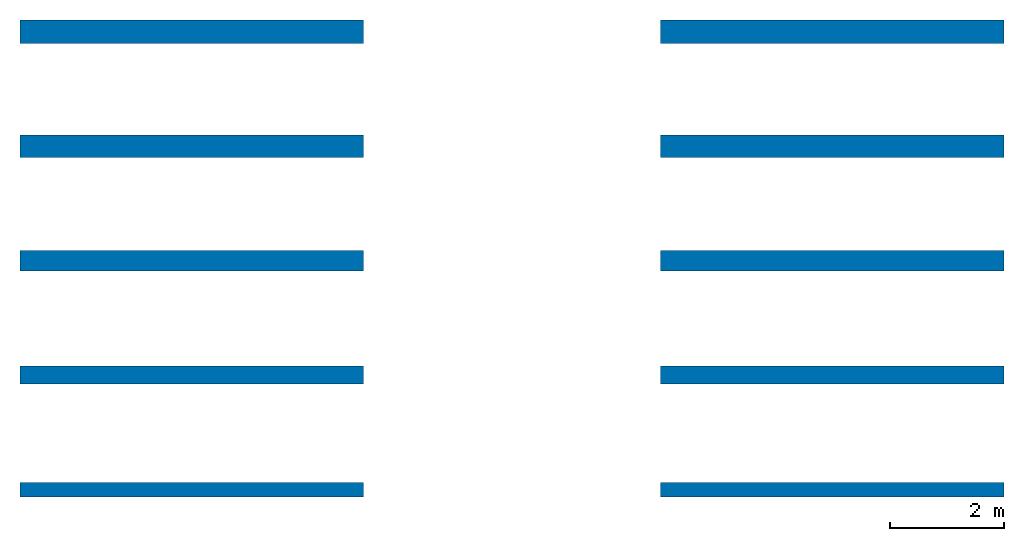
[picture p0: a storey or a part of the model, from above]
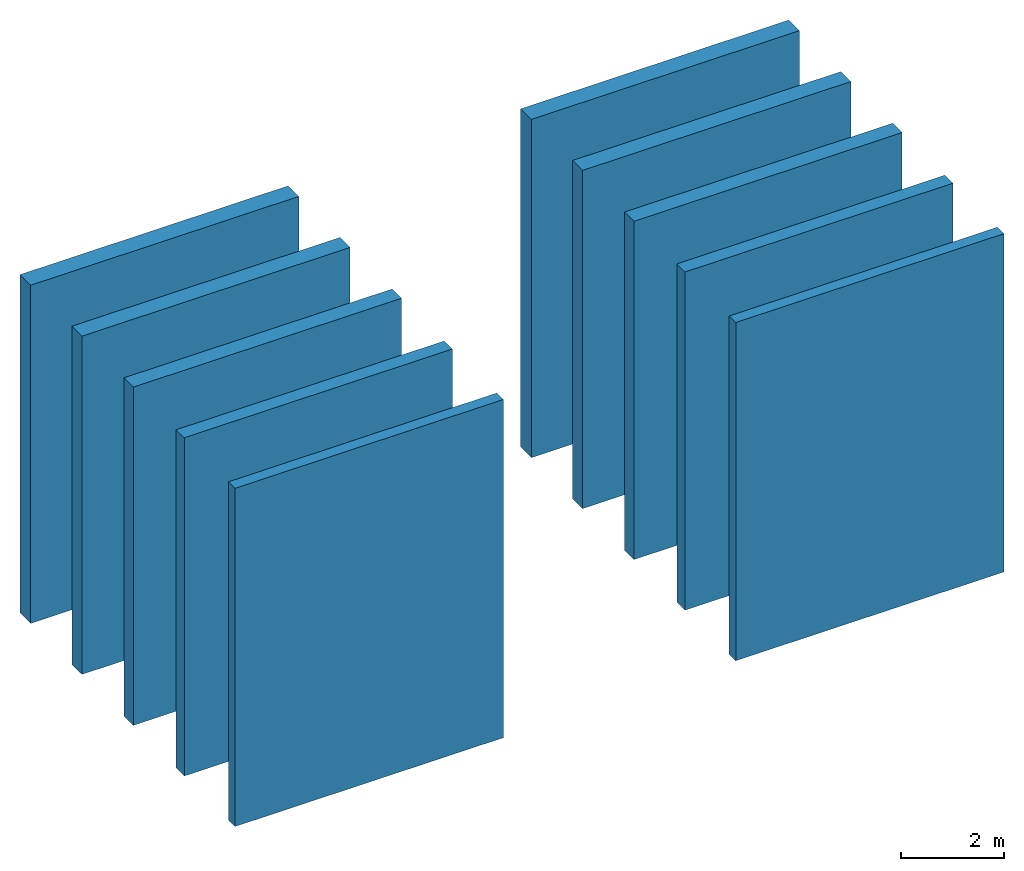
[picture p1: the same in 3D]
Properties of the parts of a building model (IFC2X3)

# File
Description: ViewDefinition [CoordinationView]
File name: Numero
Time: 2019-05-03T09:56:35
Written by: The EXPRESS Data Manager Version 5.02.0100.07 : 28 Aug 2013
Made in: 20150220_1215(x64) - Exporter 16.0.428.0 - Default UI
Comment: STEP Physical File produced by: The EXPRESS Data Manager Version 5.02.0100.07 : 28 Aug 2013 * Module: EDMstepFileFactory/EDMstandAlone * Creation date: Fri May 03 09:56:35 2019 * Host: HP-RS * Database: C:\Users\EKORU_~1\AppData\Local\Temp\{FCCCFBD5-6221-4E83-B3F0-1DA5C1BFEEF4}\ifc * Database version: 5507 * Database creation date: Fri May 03 09:56:35 2019 * Schema: IFC2X3 * Model: DataRepository.ifc * Model creation date: Fri May 03 09:56:35 2019 * Header model: DataRepository.ifc_HeaderModel * Header model creation date: Fri May 03 09:56:35 2019 * EDMuser: sdai-user * EDMgroup: sdai-group * License ID and type: 5605 : Permanent license. Expiry date: * EDMstepFileFactory options: 020000

# IfcProject, Numero
LongName: Nome; Phase: Stato

# IfcSite, Default
RefLatitude: 41, 47, 59, 999999; RefLongitude: 12, 35, 59, 999999; RefElevation: 0 mm
Altro - Categoria: Informazioni sul progetto; Data di consegna del progetto: Data; Indirizzo del progetto: Immettere l'indirizzo; Nome del cliente: Proprietario; Nome del progetto: Nome; Numero del progetto: Numero; Stato del progetto: Stato

# IfcBuilding
Pset_BuildingCommon - NumberOfStoreys: 1
Altro - Categoria: Informazioni sul progetto; Data di consegna del progetto: Data; Indirizzo del progetto: Immettere l'indirizzo; Nome del cliente: Proprietario; Nome del progetto: Nome; Numero del progetto: Numero; Stato del progetto: Stato

# IfcBuildingStorey, Livello 1
LongName: Livello 1; Elevation: 0 mm
Vincoli - Base quota altimetrica: Punto base progetto; Quota altimetrica: 0 mm
Altro - Categoria: Livelli; Famiglia: Livello: Estremità 8 mm; Famiglia e tipo: Livello: Estremità 8 mm; ID tipo: Livello: Estremità 8 mm; Tipo: Livello: Estremità 8 mm; Nome famiglia: Livello
Dati identità - Strutturale: no; Nome: Livello 1; Piano edificio: yes; Nome del tipo: Estremità 8 mm
Dimensioni - Altezza di calcolo: 0 mm
Grafica - Colore: 0; Modello di linea: Centro; Simbolo: Estremità del livello - Cerchio: Estremità del livello - Cerchio; Simbolo a estremità 1 per default: no; Simbolo a estremità 2 per default: yes; Spessore di linea: 1

# IfcWallStandardCase: Muro di base:Sistema GASBETON Sysmic sp. 254 mm muratura portante, Muro di base:Sistema GASBETON Sysmic sp. 254 mm muratura portante:139188
In: Livello 1
Type - PredefinedType: STANDARD; Material: GASBETON Multiraso interni 2 mm, GASBETON Incollarasa 5 mm, GASBETON Sysmic 240 mm, GASBETON Incollarasa 5 mm, GASBETON Multiraso interni 2 mm
Type - Altro - Categoria: Muri; Nome famiglia: Muro di base
Type - Costruzione - Funzione: Esterno; Ripiegatura agli inserti: Non ripiegare; Ripiegatura alle estremità: Nessuno; Larghezza: 254 mm
Type - Dati identità - Descrizione: Parete rifinita formata dalla seguente stratigrafia (dall'esterno verso l'interno): Multiraso interni, rete da intonaco GASBETON, Incollarasa, blocchi GASBETON Sysmic, Incollarasa, rete da intonaco GASBETON, Multira; Installation Guide: http://www.gasbeton.it/wp-content/uploads/2017/11/GASBETON-Guida-alla-progettazione.pdf; Modello: Soluzione muratura interna portante Gasbeton Sysmic; Nome del tipo: Sistema GASBETON Sysmic sp. 254 mm muratura portante; Product data url: www.gasbeton.it; Produttore: EKORU s.r.l.; Resistenza al fuoco: REI 180; EI 240; Euroclasse A1; Techinical data sheet: http://www.gasbeton.it/download/; URL: http://www.ekoru.it/; Youtube channel: https://www.youtube.com/user/bacchispa
Type - Generale - Edition number: 1; Manufacturer country: Italy; Manufacturer name: EKORU s.r.l.; Product family: walls
Type - Grafica - Colore del retino a dettaglio basso: 0
Type - Materiali e finiture - Materiale strutturale: GASBETON Sysmic; Material main: Autoclaved Aerated Concrete (AAC)
Type - Proprietà analitiche - Ruvidità: 2; Assorbimento: 0.7; Coefficiente di scambio termico (U): 0.41656; Massa termica: 499968; Resistenza termica (R): 2.40061
Altro - Famiglia: Muro di base: Sistema GASBETON Sysmic sp. 254 mm muratura portante; Famiglia e tipo: Muro di base: Sistema GASBETON Sysmic sp. 254 mm muratura portante; ID tipo: Muro di base: Sistema GASBETON Sysmic sp. 254 mm muratura portante; Tipo: Muro di base: Sistema GASBETON Sysmic sp. 254 mm muratura portante
Dimensioni - Area: 48 m2; Lunghezza: 6000 mm; Volume: 12.192 m3
Fasi - Fase di creazione: Fase 1
Strutturale - Attiva modello analitico: no; Strutturale: no; Utilizzo strutturale: Non portante
Vincoli - Delimita il locale: yes; Distanza estensione base: 0 mm; Distanza estensione superiore: 0 mm; La base è associata: no; La parte superiore è associata: no; Linea di ubicazione: Linea d'asse del muro; Offset base: 0 mm; Offset superiore: 0 mm; Relativo a massa: no; Vincolo di base: Livello: Livello 1; Altezza non collegata: 8000 mm
Pset_WallCommon - LoadBearing: no; ExtendToStructure: no; IsExternal: yes; Reference: Sistema GASBETON Sysmic sp. 254 mm muratura portante; FireRating: REI 180; EI 240; Euroclasse A1; ThermalTransmittance: 0.41656 kg/K/s3
Pset_ManufacturerTypeInformation - Manufacturer: EKORU s.r.l.

# IfcWallStandardCase: Muro di base:Sistema GASBETON Sysmic sp. 314 mm muratura portante, Muro di base:Sistema GASBETON Sysmic sp. 314 mm muratura portante:139180
In: Livello 1
Type - PredefinedType: STANDARD; Material: GASBETON Multiraso interni 2 mm, GASBETON Incollarasa 5 mm, GASBETON Sysmic 300 mm, GASBETON Incollarasa 5 mm, GASBETON Multiraso interni 2 mm
Type - Altro - Categoria: Muri; Nome famiglia: Muro di base
Type - Costruzione - Funzione: Esterno; Ripiegatura agli inserti: Non ripiegare; Ripiegatura alle estremità: Nessuno; Larghezza: 314 mm
Type - Dati identità - Descrizione: Parete rifinita formata dalla seguente stratigrafia (dall'esterno verso l'interno): Multiraso interni, rete da intonaco GASBETON, Incollarasa, blocchi GASBETON Sysmic, Incollarasa, rete da intonaco GASBETON, Multira; Installation Guide: http://www.gasbeton.it/wp-content/uploads/2017/11/GASBETON-Guida-alla-progettazione.pdf; Modello: Soluzione muratura interna portante Gasbeton Sysmic; Nome del tipo: Sistema GASBETON Sysmic sp. 314 mm muratura portante; Product data url: www.gasbeton.it; Produttore: EKORU s.r.l.; Resistenza al fuoco: REI 240; Euroclasse A1; Techinical data sheet: http://www.gasbeton.it/download/; URL: http://www.ekoru.it/; Youtube channel: https://www.youtube.com/user/bacchispa
Type - Generale - Edition number: 1; Manufacturer country: Italy; Manufacturer name: EKORU s.r.l.; Product family: walls
Type - Grafica - Colore del retino a dettaglio basso: 0
Type - Materiali e finiture - Materiale strutturale: GASBETON Sysmic; Material main: Autoclaved Aerated Concrete (AAC)
Type - Proprietà analitiche - Ruvidità: 2; Assorbimento: 0.7; Coefficiente di scambio termico (U): 0.334469; Massa termica: 621168; Resistenza termica (R): 2.98981
Altro - Famiglia: Muro di base: Sistema GASBETON Sysmic sp. 314 mm muratura portante; Famiglia e tipo: Muro di base: Sistema GASBETON Sysmic sp. 314 mm muratura portante; ID tipo: Muro di base: Sistema GASBETON Sysmic sp. 314 mm muratura portante; Tipo: Muro di base: Sistema GASBETON Sysmic sp. 314 mm muratura portante
Dimensioni - Area: 48 m2; Lunghezza: 6000 mm; Volume: 15.072 m3
Fasi - Fase di creazione: Fase 1
Strutturale - Attiva modello analitico: no; Strutturale: no; Utilizzo strutturale: Non portante
Vincoli - Delimita il locale: yes; Distanza estensione base: 0 mm; Distanza estensione superiore: 0 mm; La base è associata: no; La parte superiore è associata: no; Linea di ubicazione: Linea d'asse del muro; Offset base: 0 mm; Offset superiore: 0 mm; Relativo a massa: no; Vincolo di base: Livello: Livello 1; Altezza non collegata: 8000 mm
Pset_WallCommon - LoadBearing: no; ExtendToStructure: no; IsExternal: yes; Reference: Sistema GASBETON Sysmic sp. 314 mm muratura portante; FireRating: REI 240; Euroclasse A1; ThermalTransmittance: 0.334469 kg/K/s3
Pset_ManufacturerTypeInformation - Manufacturer: EKORU s.r.l.

# IfcWallStandardCase: Muro di base:Sistema GASBETON Sysmic sp. 364 mm muratura portante, Muro di base:Sistema GASBETON Sysmic sp. 364 mm muratura portante:139172
In: Livello 1
Type - PredefinedType: STANDARD; Material: GASBETON Multiraso interni 2 mm, GASBETON Incollarasa 5 mm, GASBETON Sysmic 350 mm, GASBETON Incollarasa 5 mm, GASBETON Multiraso interni 2 mm
Type - Altro - Categoria: Muri; Nome famiglia: Muro di base
Type - Costruzione - Funzione: Esterno; Ripiegatura agli inserti: Non ripiegare; Ripiegatura alle estremità: Nessuno; Larghezza: 364 mm
Type - Dati identità - Descrizione: Parete rifinita formata dalla seguente stratigrafia (dall'esterno verso l'interno): Multiraso interni, rete da intonaco GASBETON, Incollarasa, blocchi GASBETON Sysmic, Incollarasa, rete da intonaco GASBETON, Multira; Installation Guide: http://www.gasbeton.it/wp-content/uploads/2017/11/GASBETON-Guida-alla-progettazione.pdf; Modello: Soluzione muratura interna portante Gasbeton Sysmic; Nome del tipo: Sistema GASBETON Sysmic sp. 364 mm muratura portante; Product data url: www.gasbeton.it; Produttore: EKORU s.r.l.; Resistenza al fuoco: REI 240; Euroclasse A1; Techinical data sheet: http://www.gasbeton.it/download/; URL: http://www.ekoru.it/; Youtube channel: https://www.youtube.com/user/bacchispa
Type - Generale - Edition number: 1; Manufacturer country: Italy; Manufacturer name: EKORU s.r.l.; Product family: walls
Type - Grafica - Colore del retino a dettaglio basso: 0
Type - Materiali e finiture - Materiale strutturale: GASBETON Sysmic; Material main: Autoclaved Aerated Concrete (AAC)
Type - Proprietà analitiche - Ruvidità: 2; Assorbimento: 0.7; Coefficiente di scambio termico (U): 0.287289; Massa termica: 722168; Resistenza termica (R): 3.48081
Altro - Famiglia: Muro di base: Sistema GASBETON Sysmic sp. 364 mm muratura portante; Famiglia e tipo: Muro di base: Sistema GASBETON Sysmic sp. 364 mm muratura portante; ID tipo: Muro di base: Sistema GASBETON Sysmic sp. 364 mm muratura portante; Tipo: Muro di base: Sistema GASBETON Sysmic sp. 364 mm muratura portante
Dimensioni - Area: 48 m2; Lunghezza: 6000 mm; Volume: 17.472 m3
Fasi - Fase di creazione: Fase 1
Strutturale - Attiva modello analitico: no; Strutturale: no; Utilizzo strutturale: Non portante
Vincoli - Delimita il locale: yes; Distanza estensione base: 0 mm; Distanza estensione superiore: 0 mm; La base è associata: no; La parte superiore è associata: no; Linea di ubicazione: Linea d'asse del muro; Offset base: 0 mm; Offset superiore: 0 mm; Relativo a massa: no; Vincolo di base: Livello: Livello 1; Altezza non collegata: 8000 mm
Pset_WallCommon - LoadBearing: no; ExtendToStructure: no; IsExternal: yes; Reference: Sistema GASBETON Sysmic sp. 364 mm muratura portante; FireRating: REI 240; Euroclasse A1; ThermalTransmittance: 0.287289 kg/K/s3
Pset_ManufacturerTypeInformation - Manufacturer: EKORU s.r.l.

# IfcWallStandardCase: Muro di base:Sistema GASBETON Sysmic sp. 389 mm muratura portante, Muro di base:Sistema GASBETON Sysmic sp. 389 mm muratura portante:139164
In: Livello 1
Type - PredefinedType: STANDARD; Material: GASBETON Multiraso interni 2 mm, GASBETON Incollarasa 5 mm, GASBETON Sysmic 375 mm, GASBETON Incollarasa 5 mm, GASBETON Multiraso interni 2 mm
Type - Altro - Categoria: Muri; Nome famiglia: Muro di base
Type - Costruzione - Funzione: Esterno; Ripiegatura agli inserti: Non ripiegare; Ripiegatura alle estremità: Nessuno; Larghezza: 389 mm
Type - Dati identità - Descrizione: Parete rifinita formata dalla seguente stratigrafia (dall'esterno verso l'interno): Multiraso interni, rete da intonaco GASBETON, Incollarasa, blocchi GASBETON Sysmic, Incollarasa, rete da intonaco GASBETON, Multira; Installation Guide: http://www.gasbeton.it/wp-content/uploads/2017/11/GASBETON-Guida-alla-progettazione.pdf; Modello: Soluzione muratura interna portante Gasbeton Sysmic; Nome del tipo: Sistema GASBETON Sysmic sp. 389 mm muratura portante; Product data url: www.gasbeton.it; Produttore: EKORU s.r.l.; Resistenza al fuoco: REI 240; Euroclasse A1; Techinical data sheet: http://www.gasbeton.it/download/; URL: http://www.ekoru.it/; Youtube channel: https://www.youtube.com/user/bacchispa
Type - Generale - Edition number: 1; Manufacturer country: Italy; Manufacturer name: EKORU s.r.l.; Product family: walls
Type - Grafica - Colore del retino a dettaglio basso: 0
Type - Materiali e finiture - Materiale strutturale: GASBETON Sysmic; Material main: Autoclaved Aerated Concrete (AAC)
Type - Proprietà analitiche - Ruvidità: 2; Assorbimento: 0.7; Coefficiente di scambio termico (U): 0.268362; Massa termica: 772668; Resistenza termica (R): 3.72631
Altro - Famiglia: Muro di base: Sistema GASBETON Sysmic sp. 389 mm muratura portante; Famiglia e tipo: Muro di base: Sistema GASBETON Sysmic sp. 389 mm muratura portante; ID tipo: Muro di base: Sistema GASBETON Sysmic sp. 389 mm muratura portante; Tipo: Muro di base: Sistema GASBETON Sysmic sp. 389 mm muratura portante
Dimensioni - Area: 48 m2; Lunghezza: 6000 mm; Volume: 18.672 m3
Fasi - Fase di creazione: Fase 1
Strutturale - Attiva modello analitico: no; Strutturale: no; Utilizzo strutturale: Non portante
Vincoli - Delimita il locale: yes; Distanza estensione base: 0 mm; Distanza estensione superiore: 0 mm; La base è associata: no; La parte superiore è associata: no; Linea di ubicazione: Linea d'asse del muro; Offset base: 0 mm; Offset superiore: 0 mm; Relativo a massa: no; Vincolo di base: Livello: Livello 1; Altezza non collegata: 8000 mm
Pset_WallCommon - LoadBearing: no; ExtendToStructure: no; IsExternal: yes; Reference: Sistema GASBETON Sysmic sp. 389 mm muratura portante; FireRating: REI 240; Euroclasse A1; ThermalTransmittance: 0.268362 kg/K/s3
Pset_ManufacturerTypeInformation - Manufacturer: EKORU s.r.l.

# IfcWallStandardCase: Muro di base:Sistema GASBETON Sysmic sp. 414 mm muratura portante, Muro di base:Sistema GASBETON Sysmic sp. 414 mm muratura portante:139156
In: Livello 1
Type - PredefinedType: STANDARD; Material: GASBETON Multiraso interni 2 mm, GASBETON Incollarasa 5 mm, GASBETON Sysmic 400 mm, GASBETON Incollarasa 5 mm, GASBETON Multiraso interni 2 mm
Type - Altro - Categoria: Muri; Nome famiglia: Muro di base
Type - Costruzione - Funzione: Esterno; Larghezza: 414 mm; Ripiegatura agli inserti: Non ripiegare; Ripiegatura alle estremità: Nessuno
Type - Dati identità - Descrizione: Parete rifinita formata dalla seguente stratigrafia (dall'esterno verso l'interno): Multiraso interni, rete da intonaco GASBETON, Incollarasa, blocchi GASBETON Sysmic, Incollarasa, rete da intonaco GASBETON, Multira; Installation Guide: http://www.gasbeton.it/wp-content/uploads/2017/11/GASBETON-Guida-alla-progettazione.pdf; Modello: Soluzione muratura interna portante Gasbeton Sysmic; Nome del tipo: Sistema GASBETON Sysmic sp. 414 mm muratura portante; Product data url: www.gasbeton.it; Produttore: EKORU s.r.l.; Resistenza al fuoco: REI 240; Euroclasse A1; Techinical data sheet: http://www.gasbeton.it/download/; URL: http://www.ekoru.it/; Youtube channel: https://www.youtube.com/user/bacchispa
Type - Generale - Edition number: 1; Manufacturer country: Italy; Manufacturer name: EKORU s.r.l.; Product family: walls
Type - Grafica - Colore del retino a dettaglio basso: 0
Type - Materiali e finiture - Materiale strutturale: GASBETON Sysmic; Material main: Autoclaved Aerated Concrete (AAC)
Type - Proprietà analitiche - Assorbimento: 0.7; Coefficiente di scambio termico (U): 0.251774; Massa termica: 823168; Resistenza termica (R): 3.97181; Ruvidità: 2
Altro - Famiglia: Muro di base: Sistema GASBETON Sysmic sp. 414 mm muratura portante; Famiglia e tipo: Muro di base: Sistema GASBETON Sysmic sp. 414 mm muratura portante; ID tipo: Muro di base: Sistema GASBETON Sysmic sp. 414 mm muratura portante; Tipo: Muro di base: Sistema GASBETON Sysmic sp. 414 mm muratura portante
Dimensioni - Area: 48 m2; Lunghezza: 6000 mm; Volume: 19.872 m3
Fasi - Fase di creazione: Fase 1
Strutturale - Attiva modello analitico: no; Strutturale: no; Utilizzo strutturale: Non portante
Vincoli - Altezza non collegata: 8000 mm; Delimita il locale: yes; Distanza estensione base: 0 mm; Distanza estensione superiore: 0 mm; La base è associata: no; La parte superiore è associata: no; Linea di ubicazione: Linea d'asse del muro; Offset base: 0 mm; Offset superiore: 0 mm; Relativo a massa: no; Vincolo di base: Livello: Livello 1
Pset_WallCommon - Reference: Sistema GASBETON Sysmic sp. 414 mm muratura portante; LoadBearing: no; ExtendToStructure: no; IsExternal: yes; FireRating: REI 240; Euroclasse A1; ThermalTransmittance: 0.251774 kg/K/s3
Pset_ManufacturerTypeInformation - Manufacturer: EKORU s.r.l.

# IfcWallStandardCase: Muro di base:Sistema GASBETON Sysmic+ IDRO sp. 254 mm muratura portante, Muro di base:Sistema GASBETON Sysmic+ IDRO sp. 254 mm muratura portante:139192
In: Livello 1
Type - PredefinedType: STANDARD; Material: GASBETON Multiraso interni 2 mm, GASBETON Incollarasa 5 mm, GASBETON Sysmic 240 mm, GASBETON Incollarasa 5 mm, GASBETON Multiraso interni 2 mm
Type - Altro - Categoria: Muri; Nome famiglia: Muro di base
Type - Costruzione - Funzione: Esterno; Ripiegatura agli inserti: Non ripiegare; Ripiegatura alle estremità: Nessuno; Larghezza: 254 mm
Type - Dati identità - Descrizione: Parete rifinita formata dalla seguente stratigrafia (dall'esterno verso l'interno): Multiraso interni, rete da intonaco GASBETON, Incollarasa, blocchi GASBETON Sysmic, Incollarasa, rete da intonaco GASBETON, Multira; Installation Guide: http://www.gasbeton.it/wp-content/uploads/2017/11/GASBETON-Guida-alla-progettazione.pdf; Modello: Soluzione muratura interna portante Gasbeton Sysmic con primo corso idrofobizzato; Nome del tipo: Sistema GASBETON Sysmic+ IDRO sp. 254 mm muratura portante; Product data url: www.gasbeton.it; Produttore: EKORU s.r.l.; Resistenza al fuoco: REI 180; EI 240; Euroclasse A1; Techinical data sheet: http://www.gasbeton.it/download/; URL: http://www.ekoru.it/; Youtube channel: https://www.youtube.com/user/bacchispa
Type - Generale - Edition number: 1; Manufacturer country: Italy; Manufacturer name: EKORU s.r.l.; Product family: walls
Type - Grafica - Colore del retino a dettaglio basso: 0
Type - Materiali e finiture - Materiale strutturale: GASBETON Sysmic; Material main: Autoclaved Aerated Concrete (AAC)
Type - Proprietà analitiche - Ruvidità: 2; Assorbimento: 0.7; Coefficiente di scambio termico (U): 0.248429; Massa termica: 719808; Resistenza termica (R): 4.02529
Altro - Famiglia: Muro di base: Sistema GASBETON Sysmic+ IDRO sp. 254 mm muratura portante; Famiglia e tipo: Muro di base: Sistema GASBETON Sysmic+ IDRO sp. 254 mm muratura portante; ID tipo: Muro di base: Sistema GASBETON Sysmic+ IDRO sp. 254 mm muratura portante; Tipo: Muro di base: Sistema GASBETON Sysmic+ IDRO sp. 254 mm muratura portante
Dimensioni - Area: 48 m2; Lunghezza: 6000 mm; Volume: 12.192 m3
Fasi - Fase di creazione: Fase 1
Strutturale - Attiva modello analitico: no; Strutturale: no; Utilizzo strutturale: Non portante
Vincoli - Delimita il locale: yes; Distanza estensione base: 0 mm; Distanza estensione superiore: 0 mm; La base è associata: no; La parte superiore è associata: no; Linea di ubicazione: Linea d'asse del muro; Offset base: 0 mm; Offset superiore: 0 mm; Relativo a massa: no; Vincolo di base: Livello: Livello 1; Altezza non collegata: 8000 mm
Pset_WallCommon - LoadBearing: no; ExtendToStructure: no; IsExternal: yes; Reference: Sistema GASBETON Sysmic+ IDRO sp. 254 mm muratura portante; FireRating: REI 180; EI 240; Euroclasse A1; ThermalTransmittance: 0.248429 kg/K/s3
Pset_ManufacturerTypeInformation - Manufacturer: EKORU s.r.l.

# IfcWallStandardCase: Muro di base:Sistema GASBETON Sysmic+ IDRO sp. 314 mm muratura portante, Muro di base:Sistema GASBETON Sysmic+ IDRO sp. 314 mm muratura portante:153701
In: Livello 1
Type - PredefinedType: STANDARD; Material: GASBETON Multiraso interni 2 mm, GASBETON Incollarasa 5 mm, GASBETON Sysmic 300 mm, GASBETON Incollarasa 5 mm, GASBETON Multiraso interni 2 mm
Type - Altro - Categoria: Muri; Nome famiglia: Muro di base
Type - Costruzione - Funzione: Esterno; Ripiegatura agli inserti: Non ripiegare; Ripiegatura alle estremità: Nessuno; Larghezza: 314 mm
Type - Dati identità - Descrizione: Parete rifinita formata dalla seguente stratigrafia (dall'esterno verso l'interno): Multiraso interni, rete da intonaco GASBETON, Incollarasa, blocchi GASBETON Sysmic, Incollarasa, rete da intonaco GASBETON, Multira; Installation Guide: http://www.gasbeton.it/wp-content/uploads/2017/11/GASBETON-Guida-alla-progettazione.pdf; Modello: Soluzione muratura interna portante Gasbeton Sysmic con primo corso idrofobizzato; Nome del tipo: Sistema GASBETON Sysmic+ IDRO sp. 314 mm muratura portante; Product data url: www.gasbeton.it; Produttore: EKORU s.r.l.; Resistenza al fuoco: REI 240; Euroclasse A1; Techinical data sheet: http://www.gasbeton.it/download/; URL: http://www.ekoru.it/; Youtube channel: https://www.youtube.com/user/bacchispa
Type - Generale - Edition number: 1; Manufacturer country: Italy; Manufacturer name: EKORU s.r.l.; Product family: walls
Type - Grafica - Colore del retino a dettaglio basso: 0
Type - Materiali e finiture - Materiale strutturale: GASBETON Sysmic; Material main: Autoclaved Aerated Concrete (AAC)
Type - Proprietà analitiche - Ruvidità: 2; Assorbimento: 0.7; Coefficiente di scambio termico (U): 0.199177; Massa termica: 895968; Resistenza termica (R): 5.02065
Altro - Famiglia: Muro di base: Sistema GASBETON Sysmic+ IDRO sp. 314 mm muratura portante; Famiglia e tipo: Muro di base: Sistema GASBETON Sysmic+ IDRO sp. 314 mm muratura portante; ID tipo: Muro di base: Sistema GASBETON Sysmic+ IDRO sp. 314 mm muratura portante; Tipo: Muro di base: Sistema GASBETON Sysmic+ IDRO sp. 314 mm muratura portante
Dimensioni - Area: 48 m2; Lunghezza: 6000 mm; Volume: 15.072 m3
Fasi - Fase di creazione: Fase 1
Strutturale - Attiva modello analitico: no; Strutturale: no; Utilizzo strutturale: Non portante
Vincoli - Delimita il locale: yes; Distanza estensione base: 0 mm; Distanza estensione superiore: 0 mm; La base è associata: no; La parte superiore è associata: no; Linea di ubicazione: Linea d'asse del muro; Offset base: 0 mm; Offset superiore: 0 mm; Relativo a massa: no; Vincolo di base: Livello: Livello 1; Altezza non collegata: 8000 mm
Pset_WallCommon - LoadBearing: no; ExtendToStructure: no; IsExternal: yes; Reference: Sistema GASBETON Sysmic+ IDRO sp. 314 mm muratura portante; FireRating: REI 240; Euroclasse A1; ThermalTransmittance: 0.199177 kg/K/s3
Pset_ManufacturerTypeInformation - Manufacturer: EKORU s.r.l.

# IfcWallStandardCase: Muro di base:Sistema GASBETON Sysmic+ IDRO sp. 364 mm muratura portante, Muro di base:Sistema GASBETON Sysmic+ IDRO sp. 364 mm muratura portante:153700
In: Livello 1
Type - PredefinedType: STANDARD; Material: GASBETON Multiraso interni 2 mm, GASBETON Incollarasa 5 mm, GASBETON Sysmic 350 mm, GASBETON Incollarasa 5 mm, GASBETON Multiraso interni 2 mm
Type - Altro - Categoria: Muri; Nome famiglia: Muro di base
Type - Costruzione - Funzione: Esterno; Ripiegatura agli inserti: Non ripiegare; Ripiegatura alle estremità: Nessuno; Larghezza: 364 mm
Type - Dati identità - Descrizione: Parete rifinita formata dalla seguente stratigrafia (dall'esterno verso l'interno): Multiraso interni, rete da intonaco GASBETON, Incollarasa, blocchi GASBETON Sysmic, Incollarasa, rete da intonaco GASBETON, Multira; Installation Guide: http://www.gasbeton.it/wp-content/uploads/2017/11/GASBETON-Guida-alla-progettazione.pdf; Modello: Soluzione muratura interna portante Gasbeton Sysmic con primo corso idrofobizzato; Nome del tipo: Sistema GASBETON Sysmic+ IDRO sp. 364 mm muratura portante; Product data url: www.gasbeton.it; Produttore: EKORU s.r.l.; Resistenza al fuoco: REI 240; Euroclasse A1; Techinical data sheet: http://www.gasbeton.it/download/; URL: http://www.ekoru.it/; Youtube channel: https://www.youtube.com/user/bacchispa
Type - Generale - Edition number: 1; Manufacturer country: Italy; Manufacturer name: EKORU s.r.l.; Product family: walls
Type - Grafica - Colore del retino a dettaglio basso: 0
Type - Materiali e finiture - Materiale strutturale: GASBETON Sysmic; Material main: Autoclaved Aerated Concrete (AAC)
Type - Proprietà analitiche - Ruvidità: 2; Assorbimento: 0.7; Coefficiente di scambio termico (U): 0.170937; Massa termica: 1042768; Resistenza termica (R): 5.85012
Altro - Famiglia: Muro di base: Sistema GASBETON Sysmic+ IDRO sp. 364 mm muratura portante; Famiglia e tipo: Muro di base: Sistema GASBETON Sysmic+ IDRO sp. 364 mm muratura portante; ID tipo: Muro di base: Sistema GASBETON Sysmic+ IDRO sp. 364 mm muratura portante; Tipo: Muro di base: Sistema GASBETON Sysmic+ IDRO sp. 364 mm muratura portante
Dimensioni - Area: 48 m2; Lunghezza: 6000 mm; Volume: 17.472 m3
Fasi - Fase di creazione: Fase 1
Strutturale - Attiva modello analitico: no; Strutturale: no; Utilizzo strutturale: Non portante
Vincoli - Delimita il locale: yes; Distanza estensione base: 0 mm; Distanza estensione superiore: 0 mm; La base è associata: no; La parte superiore è associata: no; Linea di ubicazione: Linea d'asse del muro; Offset base: 0 mm; Offset superiore: 0 mm; Relativo a massa: no; Vincolo di base: Livello: Livello 1; Altezza non collegata: 8000 mm
Pset_WallCommon - LoadBearing: no; ExtendToStructure: no; IsExternal: yes; Reference: Sistema GASBETON Sysmic+ IDRO sp. 364 mm muratura portante; FireRating: REI 240; Euroclasse A1; ThermalTransmittance: 0.170937 kg/K/s3
Pset_ManufacturerTypeInformation - Manufacturer: EKORU s.r.l.

# IfcWallStandardCase: Muro di base:Sistema GASBETON Sysmic+ IDRO sp. 389 mm muratura portante, Muro di base:Sistema GASBETON Sysmic+ IDRO sp. 389 mm muratura portante:153699
In: Livello 1
Type - PredefinedType: STANDARD; Material: GASBETON Multiraso interni 2 mm, GASBETON Incollarasa 5 mm, GASBETON Sysmic 375 mm, GASBETON Incollarasa 5 mm, GASBETON Multiraso interni 2 mm
Type - Altro - Categoria: Muri; Nome famiglia: Muro di base
Type - Costruzione - Funzione: Esterno; Ripiegatura agli inserti: Non ripiegare; Ripiegatura alle estremità: Nessuno; Larghezza: 389 mm
Type - Dati identità - Descrizione: Parete rifinita formata dalla seguente stratigrafia (dall'esterno verso l'interno): Multiraso interni, rete da intonaco GASBETON, Incollarasa, blocchi GASBETON Sysmic, Incollarasa, rete da intonaco GASBETON, Multira; Installation Guide: http://www.gasbeton.it/wp-content/uploads/2017/11/GASBETON-Guida-alla-progettazione.pdf; Modello: Soluzione muratura interna portante Gasbeton Sysmic con primo corso idrofobizzato; Nome del tipo: Sistema GASBETON Sysmic+ IDRO sp. 389 mm muratura portante; Product data url: www.gasbeton.it; Produttore: EKORU s.r.l.; Resistenza al fuoco: REI 240; Euroclasse A1; Techinical data sheet: http://www.gasbeton.it/download/; URL: http://www.ekoru.it/; Youtube channel: https://www.youtube.com/user/bacchispa
Type - Generale - Edition number: 1; Manufacturer country: Italy; Manufacturer name: EKORU s.r.l.; Product family: walls
Type - Grafica - Colore del retino a dettaglio basso: 0
Type - Materiali e finiture - Materiale strutturale: GASBETON Sysmic; Material main: Autoclaved Aerated Concrete (AAC)
Type - Proprietà analitiche - Ruvidità: 2; Assorbimento: 0.7; Coefficiente di scambio termico (U): 0.15962; Massa termica: 1116168; Resistenza termica (R): 6.26486
Altro - Famiglia: Muro di base: Sistema GASBETON Sysmic+ IDRO sp. 389 mm muratura portante; Famiglia e tipo: Muro di base: Sistema GASBETON Sysmic+ IDRO sp. 389 mm muratura portante; ID tipo: Muro di base: Sistema GASBETON Sysmic+ IDRO sp. 389 mm muratura portante; Tipo: Muro di base: Sistema GASBETON Sysmic+ IDRO sp. 389 mm muratura portante
Dimensioni - Area: 48 m2; Lunghezza: 6000 mm; Volume: 18.672 m3
Fasi - Fase di creazione: Fase 1
Strutturale - Attiva modello analitico: no; Strutturale: no; Utilizzo strutturale: Non portante
Vincoli - Delimita il locale: yes; Distanza estensione base: 0 mm; Distanza estensione superiore: 0 mm; La base è associata: no; La parte superiore è associata: no; Linea di ubicazione: Linea d'asse del muro; Offset base: 0 mm; Offset superiore: 0 mm; Relativo a massa: no; Vincolo di base: Livello: Livello 1; Altezza non collegata: 8000 mm
Pset_WallCommon - LoadBearing: no; ExtendToStructure: no; IsExternal: yes; Reference: Sistema GASBETON Sysmic+ IDRO sp. 389 mm muratura portante; FireRating: REI 240; Euroclasse A1; ThermalTransmittance: 0.15962 kg/K/s3
Pset_ManufacturerTypeInformation - Manufacturer: EKORU s.r.l.

# IfcWallStandardCase: Muro di base:Sistema GASBETON Sysmic+ IDRO sp. 414 mm muratura portante, Muro di base:Sistema GASBETON Sysmic+ IDRO sp. 414 mm muratura portante:153698
In: Livello 1
Type - PredefinedType: STANDARD; Material: GASBETON Multiraso interni 2 mm, GASBETON Incollarasa 5 mm, GASBETON Sysmic 400 mm, GASBETON Incollarasa 5 mm, GASBETON Multiraso interni 2 mm
Type - Altro - Categoria: Muri; Nome famiglia: Muro di base
Type - Costruzione - Funzione: Esterno; Ripiegatura agli inserti: Non ripiegare; Ripiegatura alle estremità: Nessuno; Larghezza: 414 mm
Type - Dati identità - Descrizione: Parete rifinita formata dalla seguente stratigrafia (dall'esterno verso l'interno): tonachino colorato ai silicati/silossani, Multiraso esterni, rete da intonaco GASBETON, Multicem, blocchi GASBETON Sysmic, Incollarasa, rete da intonaco GASBETON, Multira; Installation Guide: http://www.gasbeton.it/wp-content/uploads/2017/11/GASBETON-Guida-alla-progettazione.pdf; Modello: Soluzione muratura esterna portante Gasbeton Sysmic con primo corso idrofobizzato; Nome del tipo: Sistema GASBETON Sysmic+ IDRO sp. 414 mm muratura portante; Product data url: www.gasbeton.it; Produttore: EKORU s.r.l.; Resistenza al fuoco: REI 240; Euroclasse A1; Techinical data sheet: http://www.gasbeton.it/download/; URL: http://www.ekoru.it/; Youtube channel: https://www.youtube.com/user/bacchispa
Type - Generale - Edition number: 1; Manufacturer country: Italy; Manufacturer name: EKORU s.r.l.; Product family: walls
Type - Grafica - Colore del retino a dettaglio basso: 0
Type - Materiali e finiture - Materiale strutturale: GASBETON Sysmic; Material main: Autoclaved Aerated Concrete (AAC)
Type - Proprietà analitiche - Ruvidità: 2; Assorbimento: 0.7; Coefficiente di scambio termico (U): 0.14971; Massa termica: 1189568; Resistenza termica (R): 6.6796
Altro - Famiglia: Muro di base: Sistema GASBETON Sysmic+ IDRO sp. 414 mm muratura portante; Famiglia e tipo: Muro di base: Sistema GASBETON Sysmic+ IDRO sp. 414 mm muratura portante; ID tipo: Muro di base: Sistema GASBETON Sysmic+ IDRO sp. 414 mm muratura portante; Tipo: Muro di base: Sistema GASBETON Sysmic+ IDRO sp. 414 mm muratura portante
Dimensioni - Area: 48 m2; Lunghezza: 6000 mm; Volume: 19.872 m3
Fasi - Fase di creazione: Fase 1
Strutturale - Attiva modello analitico: no; Strutturale: no; Utilizzo strutturale: Non portante
Vincoli - Delimita il locale: yes; Distanza estensione base: 0 mm; Distanza estensione superiore: 0 mm; La base è associata: no; La parte superiore è associata: no; Linea di ubicazione: Linea d'asse del muro; Offset base: 0 mm; Offset superiore: 0 mm; Relativo a massa: no; Vincolo di base: Livello: Livello 1; Altezza non collegata: 8000 mm
Pset_WallCommon - LoadBearing: no; ExtendToStructure: no; IsExternal: yes; Reference: Sistema GASBETON Sysmic+ IDRO sp. 414 mm muratura portante; FireRating: REI 240; Euroclasse A1; ThermalTransmittance: 0.14971 kg/K/s3
Pset_ManufacturerTypeInformation - Manufacturer: EKORU s.r.l.
